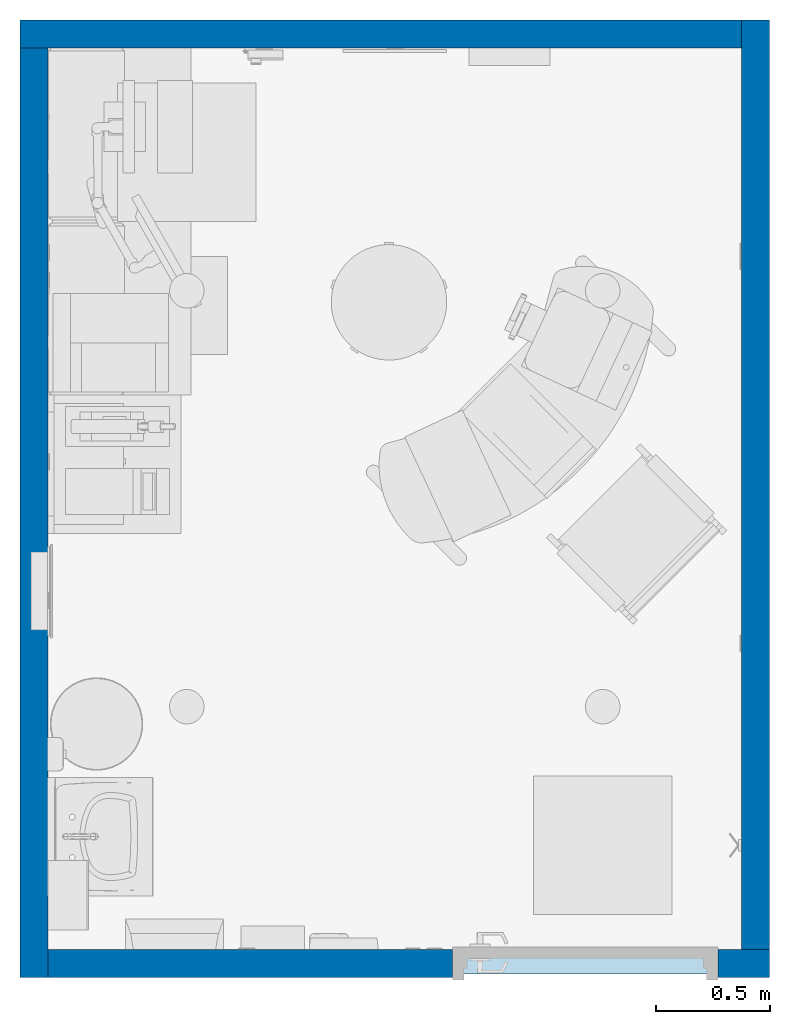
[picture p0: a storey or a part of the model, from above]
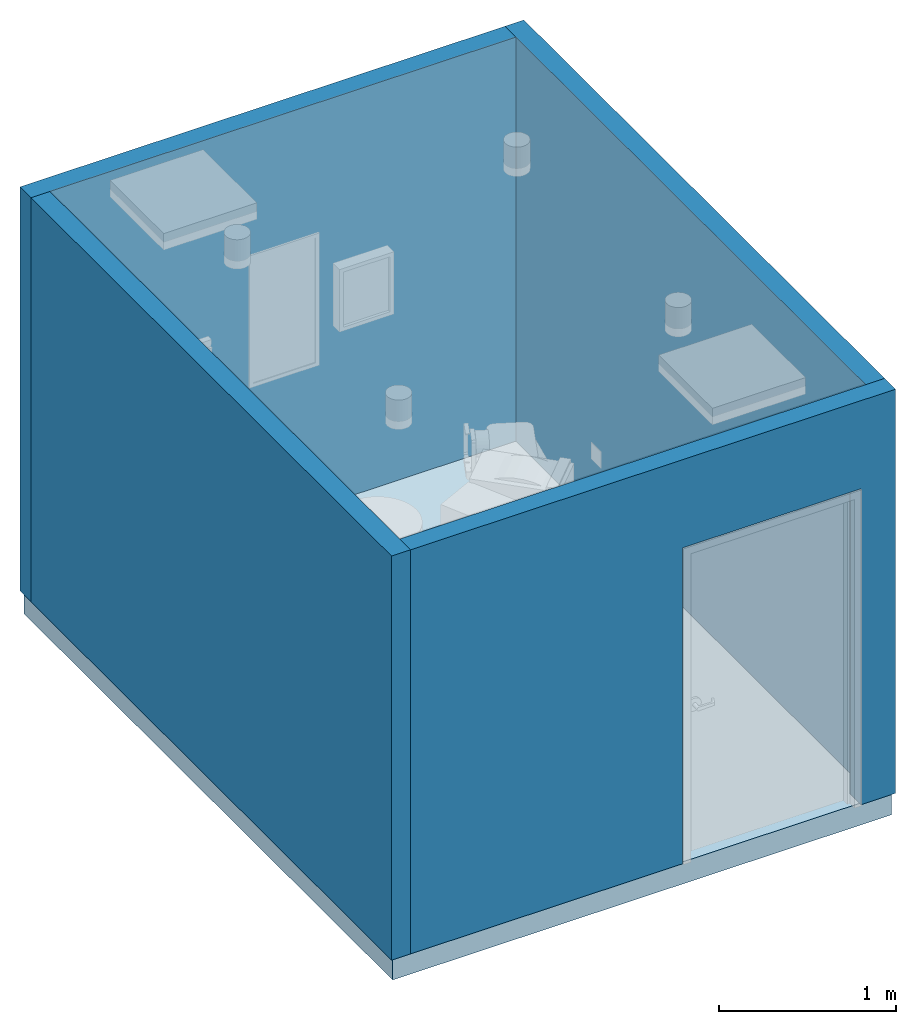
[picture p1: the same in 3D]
Properties of the parts of a building model (IFC2X3)

# File
Description: ViewDefinition [CoordinationView_V2.0]
File name: (ROOM CODE)
Time: 2018-06-28T13:51:01
Written by: The EXPRESS Data Manager Version 5.02.0100.07 : 28 Aug 2013
Made in: 20170223_1515(x64) - Exporter 18.0.0.420 - Alternate UI 18.0.0.420
Comment: STEP Physical File produced by: The EXPRESS Data Manager Version 5.02.0100.07 : 28 Aug 2013 * Module: EDMstepFileFactory/EDMstandAlone * Creation date: Thu Jun 28 13:51:01 2018 * Host: L105-OKC * Database: C:\Users\jet\AppData\Local\Temp\{237B1BBF-240B-45F4-9116-FE0858C9DA86}\ifc * Database version: 5507 * Database creation date: Thu Jun 28 13:50:59 2018 * Schema: IFC2X3 * Model: DataRepository.ifc * Model creation date: Thu Jun 28 13:51:00 2018 * Header model: DataRepository.ifc_HeaderModel * Header model creation date: Thu Jun 28 13:51:00 2018 * EDMuser: sdai-user * EDMgroup: sdai-group * License ID and type: 5605 : Permanent license. Expiry date: * EDMstepFileFactory options: 020000

# IfcProject, (ROOM CODE)
LongName: ROOM NAME & AREA; Phase: DRAFT

# IfcSite, Default
RefLatitude: 42, 21, 31, 181945; RefLongitude: -71, -3, -24, -263305; RefElevation: 0 ft

# IfcBuilding, EYE CLINIC: OPTHALMOLOGY AND OPTOMETRY SERVICES (Ch. 233)
LongName: EYE CLINIC: OPTHALMOLOGY AND OPTOMETRY SERVICES (Ch. 233)
Pset_BuildingCommon - NumberOfStoreys: 1

# IfcBuildingStorey, DATUM
In: EYE CLINIC: OPTHALMOLOGY AND OPTOMETRY SERVICES (Ch. 233)
LongName: DATUM; Elevation: 0 ft

# IfcSpace, (OPPT2)
In: DATUM
LongName: PRE-TESTING/INTAKE ROOM; InteriorOrExteriorSpace: INTERNAL
Pset_SpaceCommon - Reference: PRE-TESTING/INTAKE ROOM (OPPT2); Category: Rooms

# IfcBuildingElementProxy: 24" x 24", Supply Diffuser:24" x 24":1759673
In: (OPPT2)
Type - Classification: D3040100 Air Distribution Systems (Uniformat)
Pset_BuildingElementProxyCommon - Reference: 24" x 24"

# IfcBuildingElementProxy: 24" x 24", Return Register:24" x 24":1759672
In: (OPPT2)
Type - Classification: D3040200 Exhaust Ventilation Systems (Uniformat)
Pset_BuildingElementProxyCommon - Reference: 24" x 24"

# IfcBuildingElementProxy: A1014 - Telephone, Wall Mounted, 1 Line, With Speaker 12"x 12", A1017 - Telephone, Wall Mounted, Multi-Line, With Speaker:A1014 - Telephone, Wall Mounted, 1 Line, With Speaker 12"x 12":2119917
In: (OPPT2)
Type - Classification: VV (Uniformat)
Pset_BuildingElementProxyCommon - Reference: A1014 - Telephone, Wall Mounted, 1 Line, With Speaker 12"x 12"

# IfcBuildingElementProxy: A1066 - Mirror, Float Glass, A1066 - Mirror, Float Glass:A1066 - Mirror, Float Glass:2119922
In: (OPPT2)
Type - Classification: CC (Uniformat); Material: mirror glass, Stainless Steel
Pset_BuildingElementProxyCommon - Reference: A1066 - Mirror, Float Glass

# IfcBuildingElementProxy: A5048 - Cabinet, Medication, Security, Wall Mounted, UXXX3 - Cabinet, Medication, Security, Wall Mounted:A5048 - Cabinet, Medication, Security, Wall Mounted:2119919
In: (OPPT2)
Type - Classification: CC (Uniformat)
Pset_BuildingElementProxyCommon - Reference: A5048 - Cabinet, Medication, Security, Wall Mounted

# IfcBuildingElementProxy: A5075 - Dispenser, Soap, A5075 - Dispenser, Soap:A5075 - Dispenser, Soap:2119912
In: (OPPT2)
Type - Classification: VV (Uniformat)
Pset_BuildingElementProxyCommon - Reference: A5075 - Dispenser, Soap

# IfcBuildingElementProxy: A5077 - Dispenser, Hand Sanitizer, Hands free, A5077 - Dispenser, Hand Sanitizer, Hands free:A5077 - Dispenser, Hand Sanitizer, Hands free:2119936
In: (OPPT2)
Type - Classification: VV (Uniformat); Material: White Paint, Glass
Pset_BuildingElementProxyCommon - Reference: A5077 - Dispenser, Hand Sanitizer, Hands free

# IfcBuildingElementProxy: A5082 - Dispenser, Paper Towel, Sensor, Hands Free, A5082 - Dispenser, Paper Towel, Sensor, Hands Free:A5082 - Dispenser, Paper Towel, Sensor, Hands Free:2119899
In: (OPPT2)
Classification: CC (Uniformat)
Pset_BuildingElementProxyCommon - Reference: A5082 - Dispenser, Paper Towel, Sensor, Hands Free

# IfcBuildingElementProxy: A5107 - Dispenser, Glove, Surgical-Examination, Wall Mntd, A5107 - Dispenser, Glove, Surgical-Examination, Wall Mntd:A5107 - Dispenser, Glove, Surgical-Examination, Wall Mntd:2119898
In: (OPPT2)
Classification: VV (Uniformat)
Pset_BuildingElementProxyCommon - Reference: A5107 - Dispenser, Glove, Surgical-Examination, Wall Mntd

# IfcBuildingElementProxy: A5108 - Waste Disposal Unit, Sharps, A5108 - Waste Disposal Unit, Sharps:A5108 - Waste Disposal Unit, Sharps:2119914
In: DATUM
Classification: VV (Uniformat)
Pset_BuildingElementProxyCommon - Reference: A5108 - Waste Disposal Unit, Sharps

# IfcBuildingElementProxy: A5145 - Hook, Garment, Double, A5145 - Hook, Garment, Double:A5145 - Hook, Garment, Double:1685400
In: (OPPT2)
Type - Classification: CC (Uniformat)
Pset_BuildingElementProxyCommon - Reference: A5145 - Hook, Garment, Double

# IfcBuildingElementProxy: A5225 - Dual Flat Panel Monitor ARMS, A5225 - Dual Monitor Arms:A5225 - Dual Flat Panel Monitor ARMS:2119928
In: (OPPT2)
Type - Classification: VV (Uniformat)
Pset_BuildingElementProxyCommon - Reference: A5225 - Dual Flat Panel Monitor ARMS

# IfcBuildingElementProxy: Duplex (6)
In: (OPPT2)
Pset_BuildingElementProxyCommon - Reference: Duplex
Name (Outlet, Duplex, Wall:Duplex:...)
2395453
2395519
2395553
2395576
2452448
2462955

# IfcBuildingElementProxy: E0204 - Worksurface, with Overhd Cab & Drwrs, Wall Mtd, 24 W, E0204 - Worksurface, with Overhd Cab & Drwrs, Wall Mtd, 24 W:E0204 - Worksurface, with Overhd Cab & Drwrs, Wall Mtd, 24 W:2119900
In: (OPPT2)
Type - Classification: VV (Uniformat)
Pset_BuildingElementProxyCommon - Reference: E0204 - Worksurface, with Overhd Cab & Drwrs, Wall Mtd, 24 W

# IfcBuildingElementProxy: F0205 - Side Chair with Arms, F0205 - Side Chair with Arms:F0205 - Side Chair with Arms:2119883
In: (OPPT2)
Type - Classification: VV (Uniformat)
Pset_BuildingElementProxyCommon - Reference: F0205 - Side Chair with Arms

# IfcBuildingElementProxy: F0340 - Stool, Self Adjusting, F0340 - Stool, Self Adjusting:F0340 - Stool, Self Adjusting:2119925
In: (OPPT2)
Type - Classification: VV (Uniformat); Material: Stool caster, Stool metal, Stool cushion
Pset_BuildingElementProxyCommon - Reference: F0340 - Stool, Self Adjusting

# IfcBuildingElementProxy: F2000 - Basket, Wastepaper 16"x 16", F2000 - Basket, Wastepaper, Fire Resistant:F2000 - Basket, Wastepaper 16"x 16":2119918
In: (OPPT2)
Type - Classification: VV (Uniformat)
Pset_BuildingElementProxyCommon - Reference: F2000 - Basket, Wastepaper 16"x 16"

# IfcBuildingElementProxy: F3200 - Clock, Battery, 12in Dia, F3200 - Clock, Battery, 12in Dia:F3200 - Clock, Battery, 12in Dia:2119885
In: (OPPT2)
Type - Classification: VV (Uniformat); Material: WHITE
Pset_BuildingElementProxyCommon - Reference: F3200 - Clock, Battery, 12in Dia

# IfcBuildingElementProxy: Generic Models 20, Generic Models 20:Generic Models 20:2484888
In: (OPPT2)
Pset_BuildingElementProxyCommon - Reference: Generic Models 20

# IfcBuildingElementProxy: M1800 - Computer with Double Flat Panel Monitors, M1800 - Monitor, Computer:M1800 - Computer with Double Flat Panel Monitors:2119929
In: (OPPT2)
Type - Classification: VV (Uniformat)
Pset_BuildingElementProxyCommon - Reference: M1800 - Computer with Double Flat Panel Monitors

# IfcBuildingElementProxy: M1801 Computer, M1801 - Computer, Microprocessing, With Flat Panel Monitor:M1801 Computer:2119904
In: (OPPT2)
Type - Classification: VV (Uniformat)
Pset_BuildingElementProxyCommon - Reference: M1801 Computer

# IfcBuildingElementProxy: M1825 - Printer, Computer, M1825 - Printer, Computer:M1825 - Printer, Computer:2119902
In: (OPPT2)
Type - Classification: VV (Uniformat)
Pset_BuildingElementProxyCommon - Reference: M1825 - Printer, Computer

# IfcBuildingElementProxy: M5500 - Autorefractor, Ophthalmic, M5500 - Autorefractor, Ophthalmic:M5500 - Autorefractor, Ophthalmic:2485155
In: (OPPT2)
Type - Classification: VV (Uniformat); Material: EquipSpace
Pset_BuildingElementProxyCommon - Reference: M5500 - Autorefractor, Ophthalmic

# IfcBuildingElementProxy: M5520 - Lensometer, M5520 - Lensometer:M5520 - Lensometer:2119871
In: (OPPT2)
Type - Classification: VV (Uniformat)
Pset_BuildingElementProxyCommon - Reference: M5520 - Lensometer

# IfcBuildingElementProxy: M5525 - Lensometer, Soft Contact, M5525 - Lensometer, Soft Contact:M5525 - Lensometer, Soft Contact:2119881
In: (OPPT2)
Type - Classification: VV (Uniformat)
Pset_BuildingElementProxyCommon - Reference: M5525 - Lensometer, Soft Contact

# IfcBuildingElementProxy: M5562 - Tester, Visual Acuity, Video-Microprocessor Based, M5562 - Tester, Visual Acuity, Video-Microprocessor Based:M5562 - Tester, Visual Acuity, Video-Microprocessor Based:2119935
In: (OPPT2)
Type - Classification: VV (Uniformat)
Pset_BuildingElementProxyCommon - Reference: M5562 - Tester, Visual Acuity, Video-Microprocessor Based

# IfcBuildingElementProxy: M5575 - Tonometer, Noncontact, M5575 - Tonometer, Noncontact:M5575 - Tonometer, Noncontact:2119867
In: (OPPT2)
Type - Classification: VV (Uniformat); Material: Glass, EquipSpace
Pset_BuildingElementProxyCommon - Reference: M5575 - Tonometer, Noncontact

# IfcBuildingElementProxy: M6045 - Corneal Topography Unit, M6045 - Corneal Topography Unit:M6045 - Corneal Topography Unit:2119938
In: (OPPT2)
Type - Classification: VV (Uniformat); Material: Glass
Pset_BuildingElementProxyCommon - Reference: M6045 - Corneal Topography Unit

# IfcBuildingElementProxy: P3200 - Lavatory, Viteous China, Slab Type WSens Op Fauc, P3200 - Lavatory, Vitreous China, Slab Type WSens Op Fauc:P3200 - Lavatory, Viteous China, Slab Type WSens Op Fauc:2119903
In: (OPPT2)
Type - Classification: CC (Uniformat); Material: Vitreous China, Metal - Steel, Polished
Pset_BuildingElementProxyCommon - Reference: P3200 - Lavatory, Viteous China, Slab Type WSens Op Fauc

# IfcBuildingElementProxy: Quadraplex, Outlet, Quadraplex, Wall:Quadraplex:2395476
In: (OPPT2)
Pset_BuildingElementProxyCommon - Reference: Quadraplex

# IfcBuildingElementProxy: Single (2)
In: (OPPT2)
Type - Material: Plastic - White
Pset_BuildingElementProxyCommon - Reference: Single
Name (Switch-Single:Single:...)
2119886
2119891

# IfcBuildingElementProxy: Telephone/Data (2)
In: (OPPT2)
Pset_BuildingElementProxyCommon - Reference: Telephone/Data
Name (Outlet, Communications:Telephone/Data:...)
2395422
2462759

# IfcBuildingElementProxy: w/Overhead Cab, Wall Mtd, 48" W, E0224 - Worksurface, Computer, O-H Cab, Wall Mtd, 60in W:w/Overhead Cab, Wall Mtd, 48" W:2119901
In: (OPPT2)
Type - Classification: VV (Uniformat); Material: Finish LU Soft White 2, Vinyl 3P33 ColorGuard Pumice 2, Vinyl 3P02 ColorGuard Navy 2
Pset_BuildingElementProxyCommon - Reference: w/Overhead Cab, Wall Mtd, 48" W

# IfcCovering: Compound Ceiling:2' x 2' ACT System, Compound Ceiling:2' x 2' ACT System:1759665
In: (OPPT2)
PredefinedType: CEILING; Classification: C3030210 Suspended Ceilings - Acoustical (Uniformat); Material: Default 0.135417 ft, Acoustic Ceiling Tile 24 x 24 0.0520833 ft
Pset_CoveringCommon - Reference: 2' x 2' ACT System; Finish: Acoustic Ceiling Tile 24 x 24;; TotalThickness: 0.1875 ft

# IfcDoor: 42" x 84", Single - Flush:42" x 84":2319554
In: DATUM
Type - ParameterTakesPrecedence: no; Sizeable: no; Classification: C1020 Interior Doors (Uniformat); Material: Door - Hardware, Door - Wood Panel, Door - H.M. Frame
OverallHeight: 7.16667 ft; OverallWidth: 3.83333 ft
Pset_DoorCommon - IsExternal: no; Reference: 42" x 84"

# IfcFlowTerminal: 6" (4)
In: (OPPT2)
Type - Classification: D5020220 Lighting - Incandescent (Uniformat)
Pset_DistributionFlowElementCommon - Reference: 6"
Name (Downlight - Recessed Can:6":...)
1759670
1759671
2452629
2452630

# IfcSlab: Floor:Generic - 6", Floor:Generic - 6":1965241
In: DATUM
PredefinedType: FLOOR; Classification: B1010 Floor Construction (Uniformat); Material: Default Floor 0.5 ft
Pset_SlabCommon - Reference: Generic - 6"; IsExternal: no; LoadBearing: no; PitchAngle: 0 deg

# IfcWallStandardCase: Basic Wall:Interior - 4 7/8" (4)
In: DATUM
Type - PredefinedType: STANDARD; Material: Default Wall 0.40625 ft
Classification: B2010 Exterior Walls (Uniformat)
Pset_WallCommon - LoadBearing: no; Reference: Interior - 4 7/8"; ExtendToStructure: no; IsExternal: yes
Name (Basic Wall:Interior - 4 7/8":...)
1976728
1977018
1977251
1979906
